VERSION 5.7 ;
BUSBITCHARS "[]" ;
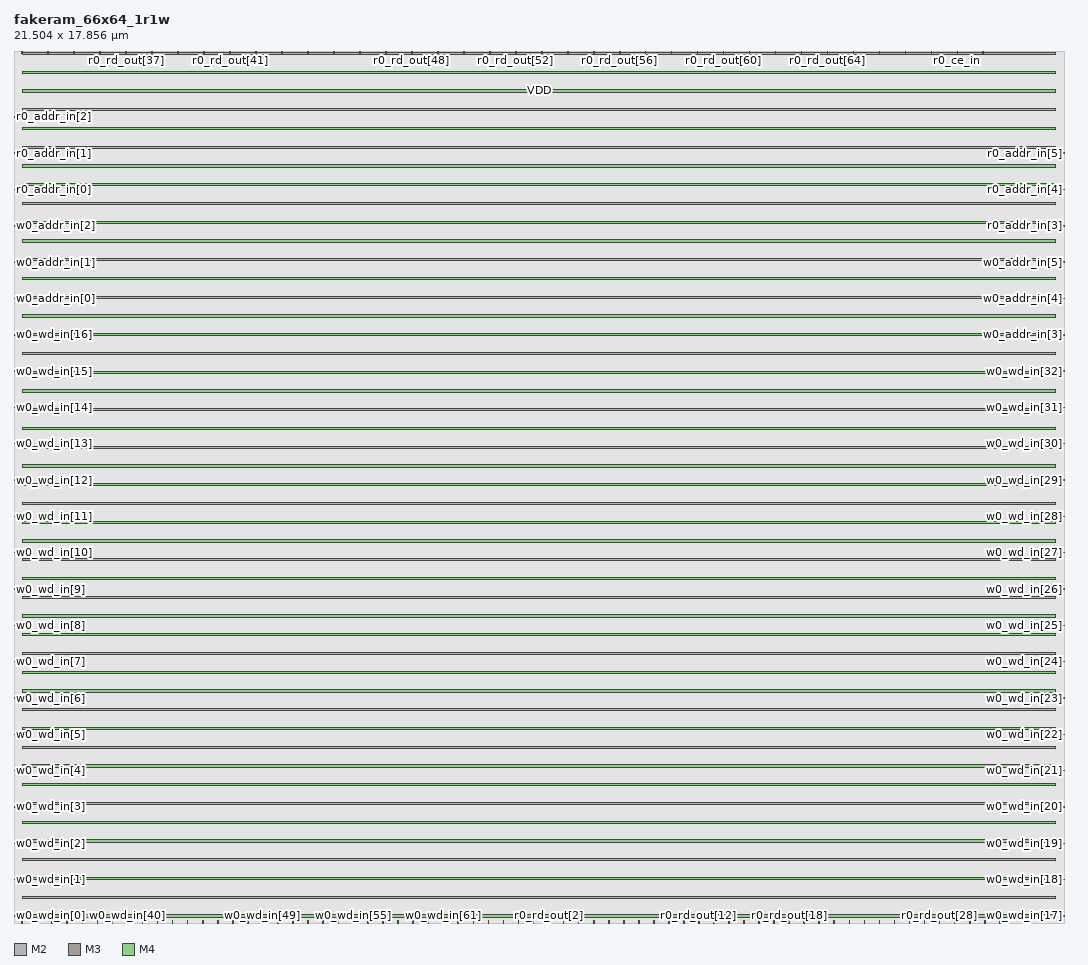
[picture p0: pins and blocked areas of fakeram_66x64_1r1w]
MACRO fakeram_66x64_1r1w
  FOREIGN fakeram_66x64_1r1w 0 0 ;
  SYMMETRY X Y R90 ;
  SIZE 21.504 BY 17.856 ;
  CLASS BLOCK ;
  PIN w0_wd_in[0]
    DIRECTION INPUT ;
    USE SIGNAL ;
    SHAPE ABUTMENT ;
    PORT
      LAYER M2 ;
      RECT 0.000 0.138 0.036 0.150 ;
    END
  END w0_wd_in[0]
  PIN w0_wd_in[1]
    DIRECTION INPUT ;
    USE SIGNAL ;
    SHAPE ABUTMENT ;
    PORT
      LAYER M2 ;
      RECT 0.000 0.882 0.036 0.894 ;
    END
  END w0_wd_in[1]
  PIN w0_wd_in[2]
    DIRECTION INPUT ;
    USE SIGNAL ;
    SHAPE ABUTMENT ;
    PORT
      LAYER M2 ;
      RECT 0.000 1.626 0.036 1.638 ;
    END
  END w0_wd_in[2]
  PIN w0_wd_in[3]
    DIRECTION INPUT ;
    USE SIGNAL ;
    SHAPE ABUTMENT ;
    PORT
      LAYER M2 ;
      RECT 0.000 2.370 0.036 2.382 ;
    END
  END w0_wd_in[3]
  PIN w0_wd_in[4]
    DIRECTION INPUT ;
    USE SIGNAL ;
    SHAPE ABUTMENT ;
    PORT
      LAYER M2 ;
      RECT 0.000 3.114 0.036 3.126 ;
    END
  END w0_wd_in[4]
  PIN w0_wd_in[5]
    DIRECTION INPUT ;
    USE SIGNAL ;
    SHAPE ABUTMENT ;
    PORT
      LAYER M2 ;
      RECT 0.000 3.858 0.036 3.870 ;
    END
  END w0_wd_in[5]
  PIN w0_wd_in[6]
    DIRECTION INPUT ;
    USE SIGNAL ;
    SHAPE ABUTMENT ;
    PORT
      LAYER M2 ;
      RECT 0.000 4.602 0.036 4.614 ;
    END
  END w0_wd_in[6]
  PIN w0_wd_in[7]
    DIRECTION INPUT ;
    USE SIGNAL ;
    SHAPE ABUTMENT ;
    PORT
      LAYER M2 ;
      RECT 0.000 5.346 0.036 5.358 ;
    END
  END w0_wd_in[7]
  PIN w0_wd_in[8]
    DIRECTION INPUT ;
    USE SIGNAL ;
    SHAPE ABUTMENT ;
    PORT
      LAYER M2 ;
      RECT 0.000 6.090 0.036 6.102 ;
    END
  END w0_wd_in[8]
  PIN w0_wd_in[9]
    DIRECTION INPUT ;
    USE SIGNAL ;
    SHAPE ABUTMENT ;
    PORT
      LAYER M2 ;
      RECT 0.000 6.834 0.036 6.846 ;
    END
  END w0_wd_in[9]
  PIN w0_wd_in[10]
    DIRECTION INPUT ;
    USE SIGNAL ;
    SHAPE ABUTMENT ;
    PORT
      LAYER M2 ;
      RECT 0.000 7.578 0.036 7.590 ;
    END
  END w0_wd_in[10]
  PIN w0_wd_in[11]
    DIRECTION INPUT ;
    USE SIGNAL ;
    SHAPE ABUTMENT ;
    PORT
      LAYER M2 ;
      RECT 0.000 8.322 0.036 8.334 ;
    END
  END w0_wd_in[11]
  PIN w0_wd_in[12]
    DIRECTION INPUT ;
    USE SIGNAL ;
    SHAPE ABUTMENT ;
    PORT
      LAYER M2 ;
      RECT 0.000 9.066 0.036 9.078 ;
    END
  END w0_wd_in[12]
  PIN w0_wd_in[13]
    DIRECTION INPUT ;
    USE SIGNAL ;
    SHAPE ABUTMENT ;
    PORT
      LAYER M2 ;
      RECT 0.000 9.810 0.036 9.822 ;
    END
  END w0_wd_in[13]
  PIN w0_wd_in[14]
    DIRECTION INPUT ;
    USE SIGNAL ;
    SHAPE ABUTMENT ;
    PORT
      LAYER M2 ;
      RECT 0.000 10.554 0.036 10.566 ;
    END
  END w0_wd_in[14]
  PIN w0_wd_in[15]
    DIRECTION INPUT ;
    USE SIGNAL ;
    SHAPE ABUTMENT ;
    PORT
      LAYER M2 ;
      RECT 0.000 11.298 0.036 11.310 ;
    END
  END w0_wd_in[15]
  PIN w0_wd_in[16]
    DIRECTION INPUT ;
    USE SIGNAL ;
    SHAPE ABUTMENT ;
    PORT
      LAYER M2 ;
      RECT 0.000 12.042 0.036 12.054 ;
    END
  END w0_wd_in[16]
  PIN w0_wd_in[17]
    DIRECTION INPUT ;
    USE SIGNAL ;
    SHAPE ABUTMENT ;
    PORT
      LAYER M2 ;
      RECT 21.468 0.138 21.504 0.150 ;
    END
  END w0_wd_in[17]
  PIN w0_wd_in[18]
    DIRECTION INPUT ;
    USE SIGNAL ;
    SHAPE ABUTMENT ;
    PORT
      LAYER M2 ;
      RECT 21.468 0.882 21.504 0.894 ;
    END
  END w0_wd_in[18]
  PIN w0_wd_in[19]
    DIRECTION INPUT ;
    USE SIGNAL ;
    SHAPE ABUTMENT ;
    PORT
      LAYER M2 ;
      RECT 21.468 1.626 21.504 1.638 ;
    END
  END w0_wd_in[19]
  PIN w0_wd_in[20]
    DIRECTION INPUT ;
    USE SIGNAL ;
    SHAPE ABUTMENT ;
    PORT
      LAYER M2 ;
      RECT 21.468 2.370 21.504 2.382 ;
    END
  END w0_wd_in[20]
  PIN w0_wd_in[21]
    DIRECTION INPUT ;
    USE SIGNAL ;
    SHAPE ABUTMENT ;
    PORT
      LAYER M2 ;
      RECT 21.468 3.114 21.504 3.126 ;
    END
  END w0_wd_in[21]
  PIN w0_wd_in[22]
    DIRECTION INPUT ;
    USE SIGNAL ;
    SHAPE ABUTMENT ;
    PORT
      LAYER M2 ;
      RECT 21.468 3.858 21.504 3.870 ;
    END
  END w0_wd_in[22]
  PIN w0_wd_in[23]
    DIRECTION INPUT ;
    USE SIGNAL ;
    SHAPE ABUTMENT ;
    PORT
      LAYER M2 ;
      RECT 21.468 4.602 21.504 4.614 ;
    END
  END w0_wd_in[23]
  PIN w0_wd_in[24]
    DIRECTION INPUT ;
    USE SIGNAL ;
    SHAPE ABUTMENT ;
    PORT
      LAYER M2 ;
      RECT 21.468 5.346 21.504 5.358 ;
    END
  END w0_wd_in[24]
  PIN w0_wd_in[25]
    DIRECTION INPUT ;
    USE SIGNAL ;
    SHAPE ABUTMENT ;
    PORT
      LAYER M2 ;
      RECT 21.468 6.090 21.504 6.102 ;
    END
  END w0_wd_in[25]
  PIN w0_wd_in[26]
    DIRECTION INPUT ;
    USE SIGNAL ;
    SHAPE ABUTMENT ;
    PORT
      LAYER M2 ;
      RECT 21.468 6.834 21.504 6.846 ;
    END
  END w0_wd_in[26]
  PIN w0_wd_in[27]
    DIRECTION INPUT ;
    USE SIGNAL ;
    SHAPE ABUTMENT ;
    PORT
      LAYER M2 ;
      RECT 21.468 7.578 21.504 7.590 ;
    END
  END w0_wd_in[27]
  PIN w0_wd_in[28]
    DIRECTION INPUT ;
    USE SIGNAL ;
    SHAPE ABUTMENT ;
    PORT
      LAYER M2 ;
      RECT 21.468 8.322 21.504 8.334 ;
    END
  END w0_wd_in[28]
  PIN w0_wd_in[29]
    DIRECTION INPUT ;
    USE SIGNAL ;
    SHAPE ABUTMENT ;
    PORT
      LAYER M2 ;
      RECT 21.468 9.066 21.504 9.078 ;
    END
  END w0_wd_in[29]
  PIN w0_wd_in[30]
    DIRECTION INPUT ;
    USE SIGNAL ;
    SHAPE ABUTMENT ;
    PORT
      LAYER M2 ;
      RECT 21.468 9.810 21.504 9.822 ;
    END
  END w0_wd_in[30]
  PIN w0_wd_in[31]
    DIRECTION INPUT ;
    USE SIGNAL ;
    SHAPE ABUTMENT ;
    PORT
      LAYER M2 ;
      RECT 21.468 10.554 21.504 10.566 ;
    END
  END w0_wd_in[31]
  PIN w0_wd_in[32]
    DIRECTION INPUT ;
    USE SIGNAL ;
    SHAPE ABUTMENT ;
    PORT
      LAYER M2 ;
      RECT 21.468 11.298 21.504 11.310 ;
    END
  END w0_wd_in[32]
  PIN w0_wd_in[33]
    DIRECTION INPUT ;
    USE SIGNAL ;
    SHAPE ABUTMENT ;
    PORT
      LAYER M3 ;
      RECT 0.161 0.000 0.175 0.042 ;
    END
  END w0_wd_in[33]
  PIN w0_wd_in[34]
    DIRECTION INPUT ;
    USE SIGNAL ;
    SHAPE ABUTMENT ;
    PORT
      LAYER M3 ;
      RECT 0.469 0.000 0.483 0.042 ;
    END
  END w0_wd_in[34]
  PIN w0_wd_in[35]
    DIRECTION INPUT ;
    USE SIGNAL ;
    SHAPE ABUTMENT ;
    PORT
      LAYER M3 ;
      RECT 0.777 0.000 0.791 0.042 ;
    END
  END w0_wd_in[35]
  PIN w0_wd_in[36]
    DIRECTION INPUT ;
    USE SIGNAL ;
    SHAPE ABUTMENT ;
    PORT
      LAYER M3 ;
      RECT 1.085 0.000 1.099 0.042 ;
    END
  END w0_wd_in[36]
  PIN w0_wd_in[37]
    DIRECTION INPUT ;
    USE SIGNAL ;
    SHAPE ABUTMENT ;
    PORT
      LAYER M3 ;
      RECT 1.393 0.000 1.407 0.042 ;
    END
  END w0_wd_in[37]
  PIN w0_wd_in[38]
    DIRECTION INPUT ;
    USE SIGNAL ;
    SHAPE ABUTMENT ;
    PORT
      LAYER M3 ;
      RECT 1.701 0.000 1.715 0.042 ;
    END
  END w0_wd_in[38]
  PIN w0_wd_in[39]
    DIRECTION INPUT ;
    USE SIGNAL ;
    SHAPE ABUTMENT ;
    PORT
      LAYER M3 ;
      RECT 2.009 0.000 2.023 0.042 ;
    END
  END w0_wd_in[39]
  PIN w0_wd_in[40]
    DIRECTION INPUT ;
    USE SIGNAL ;
    SHAPE ABUTMENT ;
    PORT
      LAYER M3 ;
      RECT 2.317 0.000 2.331 0.042 ;
    END
  END w0_wd_in[40]
  PIN w0_wd_in[41]
    DIRECTION INPUT ;
    USE SIGNAL ;
    SHAPE ABUTMENT ;
    PORT
      LAYER M3 ;
      RECT 2.625 0.000 2.639 0.042 ;
    END
  END w0_wd_in[41]
  PIN w0_wd_in[42]
    DIRECTION INPUT ;
    USE SIGNAL ;
    SHAPE ABUTMENT ;
    PORT
      LAYER M3 ;
      RECT 2.933 0.000 2.947 0.042 ;
    END
  END w0_wd_in[42]
  PIN w0_wd_in[43]
    DIRECTION INPUT ;
    USE SIGNAL ;
    SHAPE ABUTMENT ;
    PORT
      LAYER M3 ;
      RECT 3.241 0.000 3.255 0.042 ;
    END
  END w0_wd_in[43]
  PIN w0_wd_in[44]
    DIRECTION INPUT ;
    USE SIGNAL ;
    SHAPE ABUTMENT ;
    PORT
      LAYER M3 ;
      RECT 3.549 0.000 3.563 0.042 ;
    END
  END w0_wd_in[44]
  PIN w0_wd_in[45]
    DIRECTION INPUT ;
    USE SIGNAL ;
    SHAPE ABUTMENT ;
    PORT
      LAYER M3 ;
      RECT 3.857 0.000 3.871 0.042 ;
    END
  END w0_wd_in[45]
  PIN w0_wd_in[46]
    DIRECTION INPUT ;
    USE SIGNAL ;
    SHAPE ABUTMENT ;
    PORT
      LAYER M3 ;
      RECT 4.165 0.000 4.179 0.042 ;
    END
  END w0_wd_in[46]
  PIN w0_wd_in[47]
    DIRECTION INPUT ;
    USE SIGNAL ;
    SHAPE ABUTMENT ;
    PORT
      LAYER M3 ;
      RECT 4.473 0.000 4.487 0.042 ;
    END
  END w0_wd_in[47]
  PIN w0_wd_in[48]
    DIRECTION INPUT ;
    USE SIGNAL ;
    SHAPE ABUTMENT ;
    PORT
      LAYER M3 ;
      RECT 4.781 0.000 4.795 0.042 ;
    END
  END w0_wd_in[48]
  PIN w0_wd_in[49]
    DIRECTION INPUT ;
    USE SIGNAL ;
    SHAPE ABUTMENT ;
    PORT
      LAYER M3 ;
      RECT 5.089 0.000 5.103 0.042 ;
    END
  END w0_wd_in[49]
  PIN w0_wd_in[50]
    DIRECTION INPUT ;
    USE SIGNAL ;
    SHAPE ABUTMENT ;
    PORT
      LAYER M3 ;
      RECT 5.397 0.000 5.411 0.042 ;
    END
  END w0_wd_in[50]
  PIN w0_wd_in[51]
    DIRECTION INPUT ;
    USE SIGNAL ;
    SHAPE ABUTMENT ;
    PORT
      LAYER M3 ;
      RECT 5.705 0.000 5.719 0.042 ;
    END
  END w0_wd_in[51]
  PIN w0_wd_in[52]
    DIRECTION INPUT ;
    USE SIGNAL ;
    SHAPE ABUTMENT ;
    PORT
      LAYER M3 ;
      RECT 6.013 0.000 6.027 0.042 ;
    END
  END w0_wd_in[52]
  PIN w0_wd_in[53]
    DIRECTION INPUT ;
    USE SIGNAL ;
    SHAPE ABUTMENT ;
    PORT
      LAYER M3 ;
      RECT 6.321 0.000 6.335 0.042 ;
    END
  END w0_wd_in[53]
  PIN w0_wd_in[54]
    DIRECTION INPUT ;
    USE SIGNAL ;
    SHAPE ABUTMENT ;
    PORT
      LAYER M3 ;
      RECT 6.629 0.000 6.643 0.042 ;
    END
  END w0_wd_in[54]
  PIN w0_wd_in[55]
    DIRECTION INPUT ;
    USE SIGNAL ;
    SHAPE ABUTMENT ;
    PORT
      LAYER M3 ;
      RECT 6.937 0.000 6.951 0.042 ;
    END
  END w0_wd_in[55]
  PIN w0_wd_in[56]
    DIRECTION INPUT ;
    USE SIGNAL ;
    SHAPE ABUTMENT ;
    PORT
      LAYER M3 ;
      RECT 7.245 0.000 7.259 0.042 ;
    END
  END w0_wd_in[56]
  PIN w0_wd_in[57]
    DIRECTION INPUT ;
    USE SIGNAL ;
    SHAPE ABUTMENT ;
    PORT
      LAYER M3 ;
      RECT 7.553 0.000 7.567 0.042 ;
    END
  END w0_wd_in[57]
  PIN w0_wd_in[58]
    DIRECTION INPUT ;
    USE SIGNAL ;
    SHAPE ABUTMENT ;
    PORT
      LAYER M3 ;
      RECT 7.861 0.000 7.875 0.042 ;
    END
  END w0_wd_in[58]
  PIN w0_wd_in[59]
    DIRECTION INPUT ;
    USE SIGNAL ;
    SHAPE ABUTMENT ;
    PORT
      LAYER M3 ;
      RECT 8.169 0.000 8.183 0.042 ;
    END
  END w0_wd_in[59]
  PIN w0_wd_in[60]
    DIRECTION INPUT ;
    USE SIGNAL ;
    SHAPE ABUTMENT ;
    PORT
      LAYER M3 ;
      RECT 8.477 0.000 8.491 0.042 ;
    END
  END w0_wd_in[60]
  PIN w0_wd_in[61]
    DIRECTION INPUT ;
    USE SIGNAL ;
    SHAPE ABUTMENT ;
    PORT
      LAYER M3 ;
      RECT 8.785 0.000 8.799 0.042 ;
    END
  END w0_wd_in[61]
  PIN w0_wd_in[62]
    DIRECTION INPUT ;
    USE SIGNAL ;
    SHAPE ABUTMENT ;
    PORT
      LAYER M3 ;
      RECT 9.093 0.000 9.107 0.042 ;
    END
  END w0_wd_in[62]
  PIN w0_wd_in[63]
    DIRECTION INPUT ;
    USE SIGNAL ;
    SHAPE ABUTMENT ;
    PORT
      LAYER M3 ;
      RECT 9.401 0.000 9.415 0.042 ;
    END
  END w0_wd_in[63]
  PIN w0_wd_in[64]
    DIRECTION INPUT ;
    USE SIGNAL ;
    SHAPE ABUTMENT ;
    PORT
      LAYER M3 ;
      RECT 9.709 0.000 9.723 0.042 ;
    END
  END w0_wd_in[64]
  PIN w0_wd_in[65]
    DIRECTION INPUT ;
    USE SIGNAL ;
    SHAPE ABUTMENT ;
    PORT
      LAYER M3 ;
      RECT 10.017 0.000 10.031 0.042 ;
    END
  END w0_wd_in[65]
  PIN r0_rd_out[0]
    DIRECTION OUTPUT ;
    USE SIGNAL ;
    SHAPE ABUTMENT ;
    PORT
      LAYER M3 ;
      RECT 10.325 0.000 10.339 0.042 ;
    END
  END r0_rd_out[0]
  PIN r0_rd_out[1]
    DIRECTION OUTPUT ;
    USE SIGNAL ;
    SHAPE ABUTMENT ;
    PORT
      LAYER M3 ;
      RECT 10.633 0.000 10.647 0.042 ;
    END
  END r0_rd_out[1]
  PIN r0_rd_out[2]
    DIRECTION OUTPUT ;
    USE SIGNAL ;
    SHAPE ABUTMENT ;
    PORT
      LAYER M3 ;
      RECT 10.941 0.000 10.955 0.042 ;
    END
  END r0_rd_out[2]
  PIN r0_rd_out[3]
    DIRECTION OUTPUT ;
    USE SIGNAL ;
    SHAPE ABUTMENT ;
    PORT
      LAYER M3 ;
      RECT 11.249 0.000 11.263 0.042 ;
    END
  END r0_rd_out[3]
  PIN r0_rd_out[4]
    DIRECTION OUTPUT ;
    USE SIGNAL ;
    SHAPE ABUTMENT ;
    PORT
      LAYER M3 ;
      RECT 11.557 0.000 11.571 0.042 ;
    END
  END r0_rd_out[4]
  PIN r0_rd_out[5]
    DIRECTION OUTPUT ;
    USE SIGNAL ;
    SHAPE ABUTMENT ;
    PORT
      LAYER M3 ;
      RECT 11.865 0.000 11.879 0.042 ;
    END
  END r0_rd_out[5]
  PIN r0_rd_out[6]
    DIRECTION OUTPUT ;
    USE SIGNAL ;
    SHAPE ABUTMENT ;
    PORT
      LAYER M3 ;
      RECT 12.173 0.000 12.187 0.042 ;
    END
  END r0_rd_out[6]
  PIN r0_rd_out[7]
    DIRECTION OUTPUT ;
    USE SIGNAL ;
    SHAPE ABUTMENT ;
    PORT
      LAYER M3 ;
      RECT 12.481 0.000 12.495 0.042 ;
    END
  END r0_rd_out[7]
  PIN r0_rd_out[8]
    DIRECTION OUTPUT ;
    USE SIGNAL ;
    SHAPE ABUTMENT ;
    PORT
      LAYER M3 ;
      RECT 12.789 0.000 12.803 0.042 ;
    END
  END r0_rd_out[8]
  PIN r0_rd_out[9]
    DIRECTION OUTPUT ;
    USE SIGNAL ;
    SHAPE ABUTMENT ;
    PORT
      LAYER M3 ;
      RECT 13.097 0.000 13.111 0.042 ;
    END
  END r0_rd_out[9]
  PIN r0_rd_out[10]
    DIRECTION OUTPUT ;
    USE SIGNAL ;
    SHAPE ABUTMENT ;
    PORT
      LAYER M3 ;
      RECT 13.405 0.000 13.419 0.042 ;
    END
  END r0_rd_out[10]
  PIN r0_rd_out[11]
    DIRECTION OUTPUT ;
    USE SIGNAL ;
    SHAPE ABUTMENT ;
    PORT
      LAYER M3 ;
      RECT 13.713 0.000 13.727 0.042 ;
    END
  END r0_rd_out[11]
  PIN r0_rd_out[12]
    DIRECTION OUTPUT ;
    USE SIGNAL ;
    SHAPE ABUTMENT ;
    PORT
      LAYER M3 ;
      RECT 14.021 0.000 14.035 0.042 ;
    END
  END r0_rd_out[12]
  PIN r0_rd_out[13]
    DIRECTION OUTPUT ;
    USE SIGNAL ;
    SHAPE ABUTMENT ;
    PORT
      LAYER M3 ;
      RECT 14.329 0.000 14.343 0.042 ;
    END
  END r0_rd_out[13]
  PIN r0_rd_out[14]
    DIRECTION OUTPUT ;
    USE SIGNAL ;
    SHAPE ABUTMENT ;
    PORT
      LAYER M3 ;
      RECT 14.637 0.000 14.651 0.042 ;
    END
  END r0_rd_out[14]
  PIN r0_rd_out[15]
    DIRECTION OUTPUT ;
    USE SIGNAL ;
    SHAPE ABUTMENT ;
    PORT
      LAYER M3 ;
      RECT 14.945 0.000 14.959 0.042 ;
    END
  END r0_rd_out[15]
  PIN r0_rd_out[16]
    DIRECTION OUTPUT ;
    USE SIGNAL ;
    SHAPE ABUTMENT ;
    PORT
      LAYER M3 ;
      RECT 15.253 0.000 15.267 0.042 ;
    END
  END r0_rd_out[16]
  PIN r0_rd_out[17]
    DIRECTION OUTPUT ;
    USE SIGNAL ;
    SHAPE ABUTMENT ;
    PORT
      LAYER M3 ;
      RECT 15.561 0.000 15.575 0.042 ;
    END
  END r0_rd_out[17]
  PIN r0_rd_out[18]
    DIRECTION OUTPUT ;
    USE SIGNAL ;
    SHAPE ABUTMENT ;
    PORT
      LAYER M3 ;
      RECT 15.869 0.000 15.883 0.042 ;
    END
  END r0_rd_out[18]
  PIN r0_rd_out[19]
    DIRECTION OUTPUT ;
    USE SIGNAL ;
    SHAPE ABUTMENT ;
    PORT
      LAYER M3 ;
      RECT 16.177 0.000 16.191 0.042 ;
    END
  END r0_rd_out[19]
  PIN r0_rd_out[20]
    DIRECTION OUTPUT ;
    USE SIGNAL ;
    SHAPE ABUTMENT ;
    PORT
      LAYER M3 ;
      RECT 16.485 0.000 16.499 0.042 ;
    END
  END r0_rd_out[20]
  PIN r0_rd_out[21]
    DIRECTION OUTPUT ;
    USE SIGNAL ;
    SHAPE ABUTMENT ;
    PORT
      LAYER M3 ;
      RECT 16.793 0.000 16.807 0.042 ;
    END
  END r0_rd_out[21]
  PIN r0_rd_out[22]
    DIRECTION OUTPUT ;
    USE SIGNAL ;
    SHAPE ABUTMENT ;
    PORT
      LAYER M3 ;
      RECT 17.101 0.000 17.115 0.042 ;
    END
  END r0_rd_out[22]
  PIN r0_rd_out[23]
    DIRECTION OUTPUT ;
    USE SIGNAL ;
    SHAPE ABUTMENT ;
    PORT
      LAYER M3 ;
      RECT 17.409 0.000 17.423 0.042 ;
    END
  END r0_rd_out[23]
  PIN r0_rd_out[24]
    DIRECTION OUTPUT ;
    USE SIGNAL ;
    SHAPE ABUTMENT ;
    PORT
      LAYER M3 ;
      RECT 17.717 0.000 17.731 0.042 ;
    END
  END r0_rd_out[24]
  PIN r0_rd_out[25]
    DIRECTION OUTPUT ;
    USE SIGNAL ;
    SHAPE ABUTMENT ;
    PORT
      LAYER M3 ;
      RECT 18.025 0.000 18.039 0.042 ;
    END
  END r0_rd_out[25]
  PIN r0_rd_out[26]
    DIRECTION OUTPUT ;
    USE SIGNAL ;
    SHAPE ABUTMENT ;
    PORT
      LAYER M3 ;
      RECT 18.333 0.000 18.347 0.042 ;
    END
  END r0_rd_out[26]
  PIN r0_rd_out[27]
    DIRECTION OUTPUT ;
    USE SIGNAL ;
    SHAPE ABUTMENT ;
    PORT
      LAYER M3 ;
      RECT 18.641 0.000 18.655 0.042 ;
    END
  END r0_rd_out[27]
  PIN r0_rd_out[28]
    DIRECTION OUTPUT ;
    USE SIGNAL ;
    SHAPE ABUTMENT ;
    PORT
      LAYER M3 ;
      RECT 18.949 0.000 18.963 0.042 ;
    END
  END r0_rd_out[28]
  PIN r0_rd_out[29]
    DIRECTION OUTPUT ;
    USE SIGNAL ;
    SHAPE ABUTMENT ;
    PORT
      LAYER M3 ;
      RECT 19.257 0.000 19.271 0.042 ;
    END
  END r0_rd_out[29]
  PIN r0_rd_out[30]
    DIRECTION OUTPUT ;
    USE SIGNAL ;
    SHAPE ABUTMENT ;
    PORT
      LAYER M3 ;
      RECT 19.565 0.000 19.579 0.042 ;
    END
  END r0_rd_out[30]
  PIN r0_rd_out[31]
    DIRECTION OUTPUT ;
    USE SIGNAL ;
    SHAPE ABUTMENT ;
    PORT
      LAYER M3 ;
      RECT 19.873 0.000 19.887 0.042 ;
    END
  END r0_rd_out[31]
  PIN r0_rd_out[32]
    DIRECTION OUTPUT ;
    USE SIGNAL ;
    SHAPE ABUTMENT ;
    PORT
      LAYER M3 ;
      RECT 20.181 0.000 20.195 0.042 ;
    END
  END r0_rd_out[32]
  PIN r0_rd_out[33]
    DIRECTION OUTPUT ;
    USE SIGNAL ;
    SHAPE ABUTMENT ;
    PORT
      LAYER M3 ;
      RECT 0.161 17.814 0.175 17.856 ;
    END
  END r0_rd_out[33]
  PIN r0_rd_out[34]
    DIRECTION OUTPUT ;
    USE SIGNAL ;
    SHAPE ABUTMENT ;
    PORT
      LAYER M3 ;
      RECT 0.693 17.814 0.707 17.856 ;
    END
  END r0_rd_out[34]
  PIN r0_rd_out[35]
    DIRECTION OUTPUT ;
    USE SIGNAL ;
    SHAPE ABUTMENT ;
    PORT
      LAYER M3 ;
      RECT 1.225 17.814 1.239 17.856 ;
    END
  END r0_rd_out[35]
  PIN r0_rd_out[36]
    DIRECTION OUTPUT ;
    USE SIGNAL ;
    SHAPE ABUTMENT ;
    PORT
      LAYER M3 ;
      RECT 1.757 17.814 1.771 17.856 ;
    END
  END r0_rd_out[36]
  PIN r0_rd_out[37]
    DIRECTION OUTPUT ;
    USE SIGNAL ;
    SHAPE ABUTMENT ;
    PORT
      LAYER M3 ;
      RECT 2.289 17.814 2.303 17.856 ;
    END
  END r0_rd_out[37]
  PIN r0_rd_out[38]
    DIRECTION OUTPUT ;
    USE SIGNAL ;
    SHAPE ABUTMENT ;
    PORT
      LAYER M3 ;
      RECT 2.821 17.814 2.835 17.856 ;
    END
  END r0_rd_out[38]
  PIN r0_rd_out[39]
    DIRECTION OUTPUT ;
    USE SIGNAL ;
    SHAPE ABUTMENT ;
    PORT
      LAYER M3 ;
      RECT 3.353 17.814 3.367 17.856 ;
    END
  END r0_rd_out[39]
  PIN r0_rd_out[40]
    DIRECTION OUTPUT ;
    USE SIGNAL ;
    SHAPE ABUTMENT ;
    PORT
      LAYER M3 ;
      RECT 3.885 17.814 3.899 17.856 ;
    END
  END r0_rd_out[40]
  PIN r0_rd_out[41]
    DIRECTION OUTPUT ;
    USE SIGNAL ;
    SHAPE ABUTMENT ;
    PORT
      LAYER M3 ;
      RECT 4.417 17.814 4.431 17.856 ;
    END
  END r0_rd_out[41]
  PIN r0_rd_out[42]
    DIRECTION OUTPUT ;
    USE SIGNAL ;
    SHAPE ABUTMENT ;
    PORT
      LAYER M3 ;
      RECT 4.949 17.814 4.963 17.856 ;
    END
  END r0_rd_out[42]
  PIN r0_rd_out[43]
    DIRECTION OUTPUT ;
    USE SIGNAL ;
    SHAPE ABUTMENT ;
    PORT
      LAYER M3 ;
      RECT 5.481 17.814 5.495 17.856 ;
    END
  END r0_rd_out[43]
  PIN r0_rd_out[44]
    DIRECTION OUTPUT ;
    USE SIGNAL ;
    SHAPE ABUTMENT ;
    PORT
      LAYER M3 ;
      RECT 6.013 17.814 6.027 17.856 ;
    END
  END r0_rd_out[44]
  PIN r0_rd_out[45]
    DIRECTION OUTPUT ;
    USE SIGNAL ;
    SHAPE ABUTMENT ;
    PORT
      LAYER M3 ;
      RECT 6.545 17.814 6.559 17.856 ;
    END
  END r0_rd_out[45]
  PIN r0_rd_out[46]
    DIRECTION OUTPUT ;
    USE SIGNAL ;
    SHAPE ABUTMENT ;
    PORT
      LAYER M3 ;
      RECT 7.077 17.814 7.091 17.856 ;
    END
  END r0_rd_out[46]
  PIN r0_rd_out[47]
    DIRECTION OUTPUT ;
    USE SIGNAL ;
    SHAPE ABUTMENT ;
    PORT
      LAYER M3 ;
      RECT 7.609 17.814 7.623 17.856 ;
    END
  END r0_rd_out[47]
  PIN r0_rd_out[48]
    DIRECTION OUTPUT ;
    USE SIGNAL ;
    SHAPE ABUTMENT ;
    PORT
      LAYER M3 ;
      RECT 8.141 17.814 8.155 17.856 ;
    END
  END r0_rd_out[48]
  PIN r0_rd_out[49]
    DIRECTION OUTPUT ;
    USE SIGNAL ;
    SHAPE ABUTMENT ;
    PORT
      LAYER M3 ;
      RECT 8.673 17.814 8.687 17.856 ;
    END
  END r0_rd_out[49]
  PIN r0_rd_out[50]
    DIRECTION OUTPUT ;
    USE SIGNAL ;
    SHAPE ABUTMENT ;
    PORT
      LAYER M3 ;
      RECT 9.205 17.814 9.219 17.856 ;
    END
  END r0_rd_out[50]
  PIN r0_rd_out[51]
    DIRECTION OUTPUT ;
    USE SIGNAL ;
    SHAPE ABUTMENT ;
    PORT
      LAYER M3 ;
      RECT 9.737 17.814 9.751 17.856 ;
    END
  END r0_rd_out[51]
  PIN r0_rd_out[52]
    DIRECTION OUTPUT ;
    USE SIGNAL ;
    SHAPE ABUTMENT ;
    PORT
      LAYER M3 ;
      RECT 10.269 17.814 10.283 17.856 ;
    END
  END r0_rd_out[52]
  PIN r0_rd_out[53]
    DIRECTION OUTPUT ;
    USE SIGNAL ;
    SHAPE ABUTMENT ;
    PORT
      LAYER M3 ;
      RECT 10.801 17.814 10.815 17.856 ;
    END
  END r0_rd_out[53]
  PIN r0_rd_out[54]
    DIRECTION OUTPUT ;
    USE SIGNAL ;
    SHAPE ABUTMENT ;
    PORT
      LAYER M3 ;
      RECT 11.333 17.814 11.347 17.856 ;
    END
  END r0_rd_out[54]
  PIN r0_rd_out[55]
    DIRECTION OUTPUT ;
    USE SIGNAL ;
    SHAPE ABUTMENT ;
    PORT
      LAYER M3 ;
      RECT 11.865 17.814 11.879 17.856 ;
    END
  END r0_rd_out[55]
  PIN r0_rd_out[56]
    DIRECTION OUTPUT ;
    USE SIGNAL ;
    SHAPE ABUTMENT ;
    PORT
      LAYER M3 ;
      RECT 12.397 17.814 12.411 17.856 ;
    END
  END r0_rd_out[56]
  PIN r0_rd_out[57]
    DIRECTION OUTPUT ;
    USE SIGNAL ;
    SHAPE ABUTMENT ;
    PORT
      LAYER M3 ;
      RECT 12.929 17.814 12.943 17.856 ;
    END
  END r0_rd_out[57]
  PIN r0_rd_out[58]
    DIRECTION OUTPUT ;
    USE SIGNAL ;
    SHAPE ABUTMENT ;
    PORT
      LAYER M3 ;
      RECT 13.461 17.814 13.475 17.856 ;
    END
  END r0_rd_out[58]
  PIN r0_rd_out[59]
    DIRECTION OUTPUT ;
    USE SIGNAL ;
    SHAPE ABUTMENT ;
    PORT
      LAYER M3 ;
      RECT 13.993 17.814 14.007 17.856 ;
    END
  END r0_rd_out[59]
  PIN r0_rd_out[60]
    DIRECTION OUTPUT ;
    USE SIGNAL ;
    SHAPE ABUTMENT ;
    PORT
      LAYER M3 ;
      RECT 14.525 17.814 14.539 17.856 ;
    END
  END r0_rd_out[60]
  PIN r0_rd_out[61]
    DIRECTION OUTPUT ;
    USE SIGNAL ;
    SHAPE ABUTMENT ;
    PORT
      LAYER M3 ;
      RECT 15.057 17.814 15.071 17.856 ;
    END
  END r0_rd_out[61]
  PIN r0_rd_out[62]
    DIRECTION OUTPUT ;
    USE SIGNAL ;
    SHAPE ABUTMENT ;
    PORT
      LAYER M3 ;
      RECT 15.589 17.814 15.603 17.856 ;
    END
  END r0_rd_out[62]
  PIN r0_rd_out[63]
    DIRECTION OUTPUT ;
    USE SIGNAL ;
    SHAPE ABUTMENT ;
    PORT
      LAYER M3 ;
      RECT 16.121 17.814 16.135 17.856 ;
    END
  END r0_rd_out[63]
  PIN r0_rd_out[64]
    DIRECTION OUTPUT ;
    USE SIGNAL ;
    SHAPE ABUTMENT ;
    PORT
      LAYER M3 ;
      RECT 16.653 17.814 16.667 17.856 ;
    END
  END r0_rd_out[64]
  PIN r0_rd_out[65]
    DIRECTION OUTPUT ;
    USE SIGNAL ;
    SHAPE ABUTMENT ;
    PORT
      LAYER M3 ;
      RECT 17.185 17.814 17.199 17.856 ;
    END
  END r0_rd_out[65]
  PIN w0_addr_in[0]
    DIRECTION INPUT ;
    USE SIGNAL ;
    SHAPE ABUTMENT ;
    PORT
      LAYER M2 ;
      RECT 0.000 12.786 0.036 12.798 ;
    END
  END w0_addr_in[0]
  PIN w0_addr_in[1]
    DIRECTION INPUT ;
    USE SIGNAL ;
    SHAPE ABUTMENT ;
    PORT
      LAYER M2 ;
      RECT 0.000 13.530 0.036 13.542 ;
    END
  END w0_addr_in[1]
  PIN w0_addr_in[2]
    DIRECTION INPUT ;
    USE SIGNAL ;
    SHAPE ABUTMENT ;
    PORT
      LAYER M2 ;
      RECT 0.000 14.274 0.036 14.286 ;
    END
  END w0_addr_in[2]
  PIN w0_addr_in[3]
    DIRECTION INPUT ;
    USE SIGNAL ;
    SHAPE ABUTMENT ;
    PORT
      LAYER M2 ;
      RECT 21.468 12.042 21.504 12.054 ;
    END
  END w0_addr_in[3]
  PIN w0_addr_in[4]
    DIRECTION INPUT ;
    USE SIGNAL ;
    SHAPE ABUTMENT ;
    PORT
      LAYER M2 ;
      RECT 21.468 12.786 21.504 12.798 ;
    END
  END w0_addr_in[4]
  PIN w0_addr_in[5]
    DIRECTION INPUT ;
    USE SIGNAL ;
    SHAPE ABUTMENT ;
    PORT
      LAYER M2 ;
      RECT 21.468 13.530 21.504 13.542 ;
    END
  END w0_addr_in[5]
  PIN r0_addr_in[0]
    DIRECTION INPUT ;
    USE SIGNAL ;
    SHAPE ABUTMENT ;
    PORT
      LAYER M2 ;
      RECT 0.000 15.018 0.036 15.030 ;
    END
  END r0_addr_in[0]
  PIN r0_addr_in[1]
    DIRECTION INPUT ;
    USE SIGNAL ;
    SHAPE ABUTMENT ;
    PORT
      LAYER M2 ;
      RECT 0.000 15.762 0.036 15.774 ;
    END
  END r0_addr_in[1]
  PIN r0_addr_in[2]
    DIRECTION INPUT ;
    USE SIGNAL ;
    SHAPE ABUTMENT ;
    PORT
      LAYER M2 ;
      RECT 0.000 16.506 0.036 16.518 ;
    END
  END r0_addr_in[2]
  PIN r0_addr_in[3]
    DIRECTION INPUT ;
    USE SIGNAL ;
    SHAPE ABUTMENT ;
    PORT
      LAYER M2 ;
      RECT 21.468 14.274 21.504 14.286 ;
    END
  END r0_addr_in[3]
  PIN r0_addr_in[4]
    DIRECTION INPUT ;
    USE SIGNAL ;
    SHAPE ABUTMENT ;
    PORT
      LAYER M2 ;
      RECT 21.468 15.018 21.504 15.030 ;
    END
  END r0_addr_in[4]
  PIN r0_addr_in[5]
    DIRECTION INPUT ;
    USE SIGNAL ;
    SHAPE ABUTMENT ;
    PORT
      LAYER M2 ;
      RECT 21.468 15.762 21.504 15.774 ;
    END
  END r0_addr_in[5]
  PIN w0_we_in
    DIRECTION INPUT ;
    USE SIGNAL ;
    SHAPE ABUTMENT ;
    PORT
      LAYER M3 ;
      RECT 17.717 17.814 17.731 17.856 ;
    END
  END w0_we_in
  PIN w0_ce_in
    DIRECTION INPUT ;
    USE SIGNAL ;
    SHAPE ABUTMENT ;
    PORT
      LAYER M3 ;
      RECT 18.249 17.814 18.263 17.856 ;
    END
  END w0_ce_in
  PIN w0_clk
    DIRECTION INPUT ;
    USE SIGNAL ;
    SHAPE ABUTMENT ;
    PORT
      LAYER M3 ;
      RECT 18.781 17.814 18.795 17.856 ;
    END
  END w0_clk
  PIN r0_ce_in
    DIRECTION INPUT ;
    USE SIGNAL ;
    SHAPE ABUTMENT ;
    PORT
      LAYER M3 ;
      RECT 19.313 17.814 19.327 17.856 ;
    END
  END r0_ce_in
  PIN r0_clk
    DIRECTION INPUT ;
    USE SIGNAL ;
    SHAPE ABUTMENT ;
    PORT
      LAYER M3 ;
      RECT 19.845 17.814 19.859 17.856 ;
    END
  END r0_clk
  PIN VSS
    DIRECTION INOUT ;
    USE GROUND ;
    PORT
      LAYER M4 ;
      RECT 0.168 0.120 21.336 0.168 ;
      RECT 0.168 0.504 21.336 0.552 ;
      RECT 0.168 0.888 21.336 0.936 ;
      RECT 0.168 1.272 21.336 1.320 ;
      RECT 0.168 1.656 21.336 1.704 ;
      RECT 0.168 2.040 21.336 2.088 ;
      RECT 0.168 2.424 21.336 2.472 ;
      RECT 0.168 2.808 21.336 2.856 ;
      RECT 0.168 3.192 21.336 3.240 ;
      RECT 0.168 3.576 21.336 3.624 ;
      RECT 0.168 3.960 21.336 4.008 ;
      RECT 0.168 4.344 21.336 4.392 ;
      RECT 0.168 4.728 21.336 4.776 ;
      RECT 0.168 5.112 21.336 5.160 ;
      RECT 0.168 5.496 21.336 5.544 ;
      RECT 0.168 5.880 21.336 5.928 ;
      RECT 0.168 6.264 21.336 6.312 ;
      RECT 0.168 6.648 21.336 6.696 ;
      RECT 0.168 7.032 21.336 7.080 ;
      RECT 0.168 7.416 21.336 7.464 ;
      RECT 0.168 7.800 21.336 7.848 ;
      RECT 0.168 8.184 21.336 8.232 ;
      RECT 0.168 8.568 21.336 8.616 ;
      RECT 0.168 8.952 21.336 9.000 ;
      RECT 0.168 9.336 21.336 9.384 ;
      RECT 0.168 9.720 21.336 9.768 ;
      RECT 0.168 10.104 21.336 10.152 ;
      RECT 0.168 10.488 21.336 10.536 ;
      RECT 0.168 10.872 21.336 10.920 ;
      RECT 0.168 11.256 21.336 11.304 ;
      RECT 0.168 11.640 21.336 11.688 ;
      RECT 0.168 12.024 21.336 12.072 ;
      RECT 0.168 12.408 21.336 12.456 ;
      RECT 0.168 12.792 21.336 12.840 ;
      RECT 0.168 13.176 21.336 13.224 ;
      RECT 0.168 13.560 21.336 13.608 ;
      RECT 0.168 13.944 21.336 13.992 ;
      RECT 0.168 14.328 21.336 14.376 ;
      RECT 0.168 14.712 21.336 14.760 ;
      RECT 0.168 15.096 21.336 15.144 ;
      RECT 0.168 15.480 21.336 15.528 ;
      RECT 0.168 15.864 21.336 15.912 ;
      RECT 0.168 16.248 21.336 16.296 ;
      RECT 0.168 16.632 21.336 16.680 ;
      RECT 0.168 17.016 21.336 17.064 ;
      RECT 0.168 17.400 21.336 17.448 ;
      RECT 0.168 17.784 21.336 17.832 ;
    END
  END VSS
  PIN VDD
    DIRECTION INOUT ;
    USE POWER ;
    PORT
      LAYER M4 ;
      RECT 0.168 0.120 21.336 0.168 ;
      RECT 0.168 0.504 21.336 0.552 ;
      RECT 0.168 0.888 21.336 0.936 ;
      RECT 0.168 1.272 21.336 1.320 ;
      RECT 0.168 1.656 21.336 1.704 ;
      RECT 0.168 2.040 21.336 2.088 ;
      RECT 0.168 2.424 21.336 2.472 ;
      RECT 0.168 2.808 21.336 2.856 ;
      RECT 0.168 3.192 21.336 3.240 ;
      RECT 0.168 3.576 21.336 3.624 ;
      RECT 0.168 3.960 21.336 4.008 ;
      RECT 0.168 4.344 21.336 4.392 ;
      RECT 0.168 4.728 21.336 4.776 ;
      RECT 0.168 5.112 21.336 5.160 ;
      RECT 0.168 5.496 21.336 5.544 ;
      RECT 0.168 5.880 21.336 5.928 ;
      RECT 0.168 6.264 21.336 6.312 ;
      RECT 0.168 6.648 21.336 6.696 ;
      RECT 0.168 7.032 21.336 7.080 ;
      RECT 0.168 7.416 21.336 7.464 ;
      RECT 0.168 7.800 21.336 7.848 ;
      RECT 0.168 8.184 21.336 8.232 ;
      RECT 0.168 8.568 21.336 8.616 ;
      RECT 0.168 8.952 21.336 9.000 ;
      RECT 0.168 9.336 21.336 9.384 ;
      RECT 0.168 9.720 21.336 9.768 ;
      RECT 0.168 10.104 21.336 10.152 ;
      RECT 0.168 10.488 21.336 10.536 ;
      RECT 0.168 10.872 21.336 10.920 ;
      RECT 0.168 11.256 21.336 11.304 ;
      RECT 0.168 11.640 21.336 11.688 ;
      RECT 0.168 12.024 21.336 12.072 ;
      RECT 0.168 12.408 21.336 12.456 ;
      RECT 0.168 12.792 21.336 12.840 ;
      RECT 0.168 13.176 21.336 13.224 ;
      RECT 0.168 13.560 21.336 13.608 ;
      RECT 0.168 13.944 21.336 13.992 ;
      RECT 0.168 14.328 21.336 14.376 ;
      RECT 0.168 14.712 21.336 14.760 ;
      RECT 0.168 15.096 21.336 15.144 ;
      RECT 0.168 15.480 21.336 15.528 ;
      RECT 0.168 15.864 21.336 15.912 ;
      RECT 0.168 16.248 21.336 16.296 ;
      RECT 0.168 16.632 21.336 16.680 ;
      RECT 0.168 17.016 21.336 17.064 ;
      RECT 0.168 17.400 21.336 17.448 ;
      RECT 0.168 17.784 21.336 17.832 ;
    END
  END VDD
  OBS
    LAYER M1 ;
    RECT 0 0 21.504 17.856 ;
    LAYER M2 ;
    RECT 0 0 21.504 17.856 ;
    LAYER M3 ;
    RECT 0 0 21.504 17.856 ;
    LAYER M4 ;
    RECT 0 0 21.504 17.856 ;
  END
END fakeram_66x64_1r1w

END LIBRARY
